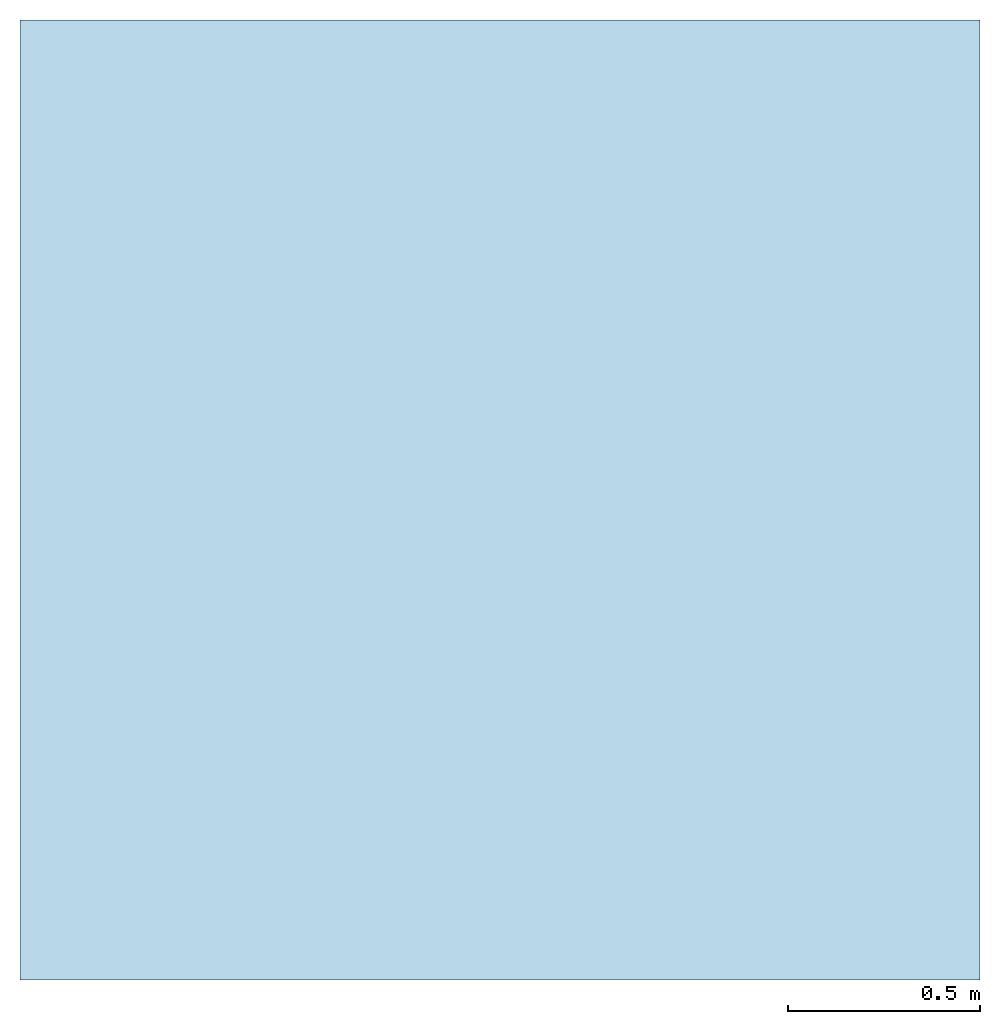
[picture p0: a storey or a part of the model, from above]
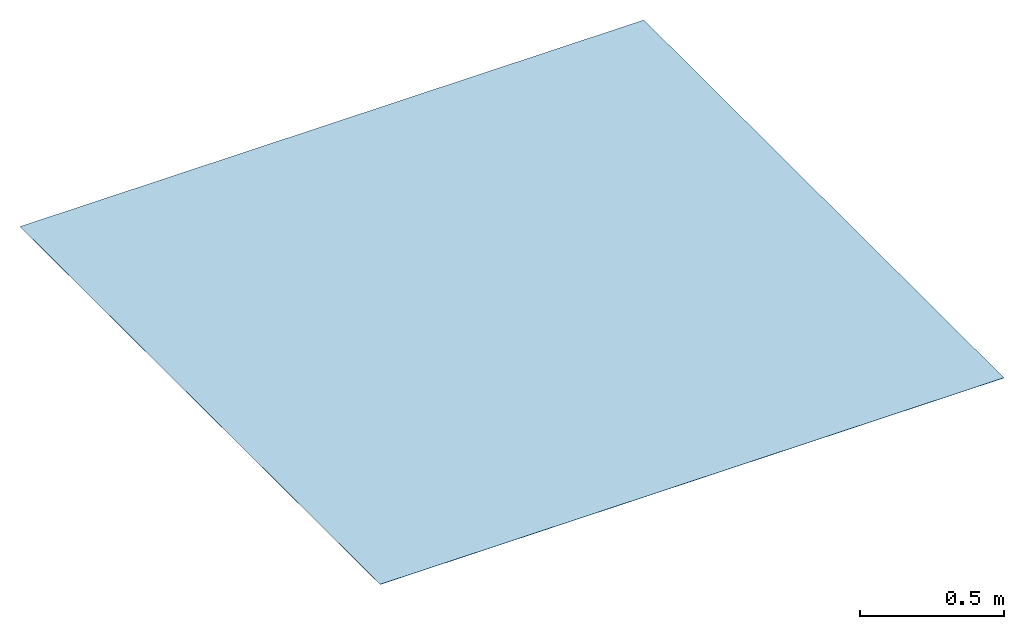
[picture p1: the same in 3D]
Properties of the parts of a building model (IFC2X3)

# File
Description: ViewDefinition[CoordinationView]
Time: 2018-01-30T09:29:22
Author: NBS
Written by: Xbim.Ifc File Processor version 2.4.1.0
Made in: Xbim version 2.4.1.0
Authorization: Add company name here

# IfcSlab: NBS_DeltaMembranes_CldApBitmnSol_MemtechLGB
In: Default building
Type - PredefinedType: FLOOR; Material: NBS_DeltaMembranes_CldApBitmnSol_MemtechLGB 1 mm
Type - xbim_MaterialFunctionAssignment - MaterialFunctionAssignment: 0: Substrate
Type - COBie - AccessibilityPerformance: n/a; AssetType: Fixed; Category: Pr_35_31_68_16:Cold-applied bitumen solutions; CodePerformance: BR211, CIRIA, BSI (BS 8485:2015); Color: Green; Constituents: n/a; Description: MEMTECH LGB is a ready for use specialist styrene butadiene latex based liquid applied gas membrane. It offers a simple, continuous passive gas prevention barrier against the ingress of Methane, Carbon Dioxide, Radon, Ground Gas, VOC, air & moisture into buildings. MEMTECH LGB also acts as a waterproofing membrane complying with the requirement C2 and C4 schedule 1 of the Building Regulations 1991 for England and Wales; DurationUnit: year; ExpectedLife: Life time of the building; Features: As the product is a barrier to moisture it can be used as a DPM on floors and walls; Grade: n/a; Manufacturer: info@deltamembranes.com; ModelNumber: n/a; ModelReference: Memtech LGB; Name: ColdAppliedBitumenSolutions_MemtechLGB_DeltaMembranes; NominalHeight: 0 mm; NominalLength: 1 mm; NominalWidth: 0 mm; ReplacementCost: n/a; Shape: n/a; Size: n/a; SustainabilityPerformance: n/a; WarrantyDescription: n/a; WarrantyDurationLabor: n/a; WarrantyDurationParts: 10; WarrantyDurationUnit: year; WarrantyGuarantorLabor: n/a; WarrantyGuarantorParts: info@deltamembranes.com
Type - Pset_CoveringCommon - AcousticRating: n/a; Combustible: yes; Finish: n/a; FireRating: n/a; FlammabilityRating: n/a; FragilityRating: n/a; Material: Advanced SBS with speciality additives; Reference: n/a; SurfaceSpreadOfFlame: n/a; TotalThickness: 0 mm
Type - NBS_Data - Application: MEMTECH LGB may be applied by brush, roller or airless spray; ApplicationTemperature: The membrane should not be applied in temperatures below 7°C; ChemicalComposition: Advanced SBS with speciality additives; Compatability: MEMTECH LGB is compatible with loose laid membranes supplied by Delta Membrane Systems Ltd, such as MEMTE CH M1, MEMTECH R1, MS M embranes, and MEMTECH-TITAN; Coverage: A minimum dry coated thickness of 1.0 mm is needed to provide a gas barrier. To achieve 1.0 mm thickness, a total of 2 kg/m² is required, therefore a 15 kg tub will cover an area of 7.5 m²; FormSupplied: Viscous Liquid; MethanePermeability: BS EN ISO 15105-1; PackSize: 15 kg; RadonPermeability: >1.0 mm applied thickness provides a complete barrier to Radon; ThirdPartyCertification: n/a; WaterTightness: EN 1296, EN 1367, EN 1928
Type - NBS_General - Author: NBS; BIMObjectName: NBS_DeltaMembranes_ColdAppliedBitumenSolutions_MemtechLGB; ManufacturerName: Delta Membranes; ManufacturerURL: www.deltamembranes.com/; NBSCertification: www.nationalbimlibrary.com/cert/zm4lm4ci; NBSDescription: Cold applied bitumen solutions; NBSNote: n/a; NBSOfficeMasterTag: n/a; NBSReference: 45-55-12/365; NBSTypeID: n/a; ProductInformation: www.deltamembranes.com/products/liquid-applied-gas-membrane/#; Revision: n/a; Uniclass2015Code: Pr_35_31_68_16; Uniclass2015Title: Cold-applied bitumen solutions; Uniclass2015Version: Products v1.8; Version: 1
Type - IFC - IfcExportAs: IfcCoveringType; IfcExportType: MEMBRANE
COBie - AssetIdentifier: n/a; BarCode: n/a; InstallationDate: 1900-12-31T23:59:59; SerialNumber: n/a; TagNumber: n/a; WarrantyStartDate: 1900-12-31T23:59:59
